# Copyright 2020 The SkyWater PDK Authors
#
# Licensed under the Apache License, Version 2.0 (the "License");
# you may not use this file except in compliance with the License.
# You may obtain a copy of the License at
#
#     https://www.apache.org/licenses/LICENSE-2.0
#
# Unless required by applicable law or agreed to in writing, software
# distributed under the License is distributed on an "AS IS" BASIS,
# WITHOUT WARRANTIES OR CONDITIONS OF ANY KIND, either express or implied.
# See the License for the specific language governing permissions and
# limitations under the License.
#
# SPDX-License-Identifier: Apache-2.0

VERSION 5.7 ;

BUSBITCHARS "[]" ;
DIVIDERCHAR "/" ;

UNITS
  TIME NANOSECONDS 1 ;
  CAPACITANCE PICOFARADS 1 ;
  RESISTANCE OHMS 1 ;
  DATABASE MICRONS 1000 ;
END UNITS

MANUFACTURINGGRID 0.005 ;
USEMINSPACING OBS OFF ;

PROPERTYDEFINITIONS
  LAYER LEF58_TYPE STRING ;
END PROPERTYDEFINITIONS

# High density, single height
SITE unithd
  SYMMETRY Y ;
  CLASS CORE ;
  SIZE 0.46 BY 2.72 ;
END unithd
LAYER nwell
  TYPE MASTERSLICE ;
  PROPERTY LEF58_TYPE "TYPE NWELL ;" ;
END nwell
LAYER pwell
  TYPE MASTERSLICE ;
  PROPERTY LEF58_TYPE "TYPE PWELL ;" ;
END pwell
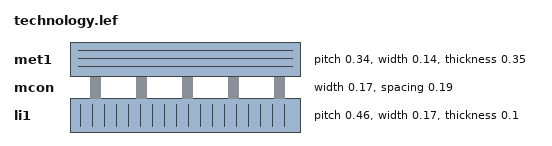
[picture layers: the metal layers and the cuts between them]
LAYER li1
  TYPE ROUTING ;
  DIRECTION VERTICAL ;

  PITCH 0.46 0.34 ;
  OFFSET 0.23 0.17 ;

  WIDTH 0.17 ;          # LI 1
  # SPACING  0.17 ;     # LI 2
  SPACINGTABLE
     PARALLELRUNLENGTH 0
     WIDTH 0 0.17 ;
  AREA 0.0561 ;         # LI 6
  THICKNESS 0.1 ;
  EDGECAPACITANCE 40.697E-6 ;
  CAPACITANCE CPERSQDIST 36.9866E-6 ;
  RESISTANCE RPERSQ 12.8 ;

END li1
LAYER mcon
  TYPE CUT ;

  WIDTH 0.17 ;                # Mcon 1
  SPACING 0.19 ;              # Mcon 2
  ENCLOSURE BELOW 0 0 ;       # Mcon 4
  ENCLOSURE ABOVE 0.03 0.06 ; # Met1 4 / Met1 5
  RESISTANCE 9.30 ;


END mcon
LAYER met1
  TYPE ROUTING ;
  DIRECTION HORIZONTAL ;

  PITCH 0.34 ;
  OFFSET 0.17 ;

  WIDTH 0.14 ;                     # Met1 1
  # SPACING 0.14 ;                 # Met1 2
  # SPACING 0.28 RANGE 3.001 100 ; # Met1 3b
  SPACINGTABLE
     PARALLELRUNLENGTH 0
     WIDTH 0 0.14
     WIDTH 3 0.28 ;
  AREA 0.083 ;                     # Met1 6
  THICKNESS 0.35 ;
  MINENCLOSEDAREA 0.14 ;


  EDGECAPACITANCE 40.567E-6 ;
  CAPACITANCE CPERSQDIST 25.7784E-6 ;
  MAXIMUMDENSITY 70 ;
  DENSITYCHECKWINDOW 700 700 ;
  DENSITYCHECKSTEP 70 ;

  RESISTANCE RPERSQ 0.125 ;
END met1
VIA L1M1_PR DEFAULT
  LAYER mcon ;
  RECT -0.085 -0.085 0.085 0.085 ;
  LAYER li1 ;
  RECT -0.085 -0.085 0.085 0.085 ;
  LAYER met1 ;
  RECT -0.145 -0.115 0.145 0.115 ;
END L1M1_PR
END LIBRARY
